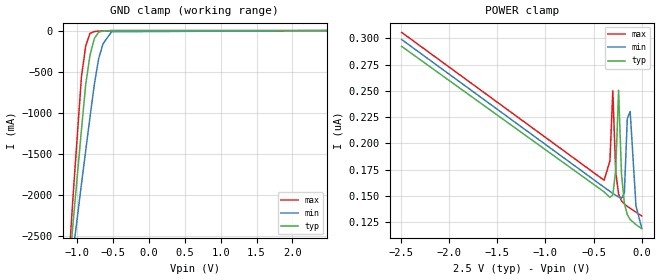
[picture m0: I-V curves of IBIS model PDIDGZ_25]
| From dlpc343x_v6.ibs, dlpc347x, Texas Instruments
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[Model]  PDIDGZ_25
Model_type Input
Polarity   Non-Inverting
Vinl =   0.7000V
Vinh =   1.7000V
C_comp   3.3398pF   3.2159pF   3.4802pF
[Temperature Range]   25.0000   0.1250k   -40.0000
[Voltage Range]   2.5000V   2.2500V   2.7500V
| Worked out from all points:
|   GND clamp passes 1 mA (typ) near -0.53 V on its own axis
[GND_clamp]
|Voltage   I(typ)   I(min)   I(max)
-2.5V     -17.18A    -13.18A    -22.65A
-1.18V    -3.58A     -3.573A    -3.716A
-1.12V    -2.977A    -3.144A    -2.882A
-1.06V    -2.378A    -2.717A    -2.061A
-940mV    -1.209A    -1.873A    -563mA
-880mV    -653.4mA   -1.458A    -184.6mA
-820mV    -295.6mA   -1.051A    -33.54mA
-760mV    -96.47mA   -655.6mA   -11.44mA
-700mV    -19.54mA   -341.9mA   -6.793mA
-640mV    -4.897mA   -162.3mA   -3.856mA
-520mV    -740.7uA   -14.11mA   -622uA
2.48V     117.6nA    148.6nA    114.5nA
[POWER_clamp]
|Voltage   I(typ)   I(min)   I(max)
-2.49V    292.5nA    299nA      305.8nA
-390mV    153.9nA    158.3nA    165nA
-330mV    148.7nA    154.4nA    183.4nA
-300mV    151nA      152.5nA    250.1nA
-270mV    174.3nA    150.7nA    172.8nA
-240mV    250.7nA    149.1nA    151.9nA
-210mV    171nA      147.7nA    145.3nA
-180mV    142.9nA    153nA      142.4nA
-150mV    132.3nA    223.4nA    140.2nA
-120mV    127.6nA    230.5nA    138.3nA
-60mV     122.7nA    140.6nA    134.6nA
0V        118.9nA    119.4nA    131nA
